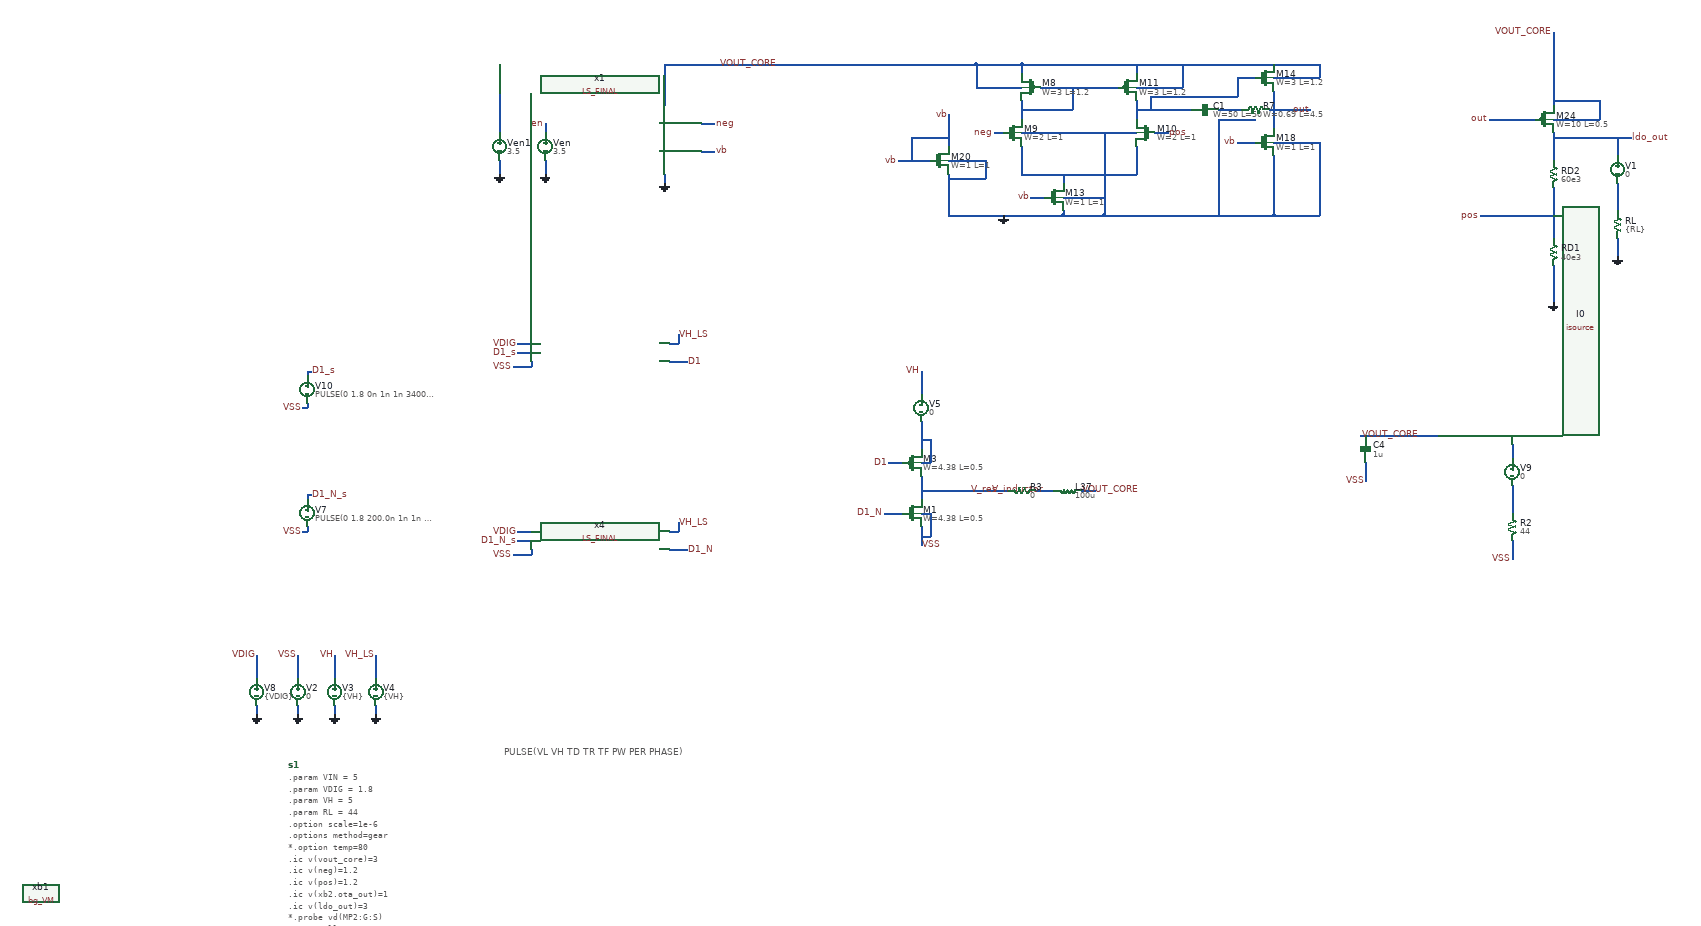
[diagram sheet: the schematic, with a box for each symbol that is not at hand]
v {xschem version=3.4.2 file_version=1.2
}
G {}
K {}
V {}
S {}
E {}
T {PULSE(VL VH TD TR TF PW PER PHASE) } -380 -120 0 0 0.4 0.4 {}
N -830 -210 -830 -190 { lab=GND}
N -830 -320 -830 -270 { lab=VSS}
N -750 -210 -750 -190 { lab=GND}
N -750 -320 -750 -270 { lab=VH}
N 1490 -800 1550 -800 {
lab=VOUT_CORE}
N 1610 -800 1660 -800 {
lab=VOUT_CORE}
N 1550 -800 1610 -800 {
lab=VOUT_CORE}
N 1820 -570 1820 -530 {
lab=VSS}
N 1820 -780 1820 -750 {
lab=#net1}
N -920 -210 -920 -190 { lab=GND}
N -920 -320 -920 -270 { lab=VDIG}
N -660 -210 -660 -190 { lab=GND}
N -660 -320 -660 -270 { lab=VH_LS}
N 1820 -690 1820 -630 {
lab=#net2}
N 1500 -740 1500 -700 {
lab=VSS}
N -290 -1480 -290 -1460 { lab=en}
N -290 -1400 -290 -1370 {
lab=GND}
N -30 -1610 -30 -1520 {
lab=VOUT_CORE}
N 750 -1610 750 -1590 { lab=VOUT_CORE}
N 750 -1610 1000 -1610 { lab=VOUT_CORE}
N 1000 -1610 1000 -1590 { lab=VOUT_CORE}
N 1000 -1530 1000 -1490 { lab=#net3}
N 790 -1560 960 -1560 { lab=#net4}
N 750 -1530 750 -1490 { lab=#net4}
N 750 -1430 750 -1370 { lab=#net5}
N 750 -1370 1000 -1370 { lab=#net5}
N 1000 -1430 1000 -1370 { lab=#net5}
N 840 -1370 840 -1350 { lab=#net5}
N 750 -1460 1000 -1460 { lab=GND}
N 930 -1460 930 -1280 { lab=GND}
N 840 -1280 930 -1280 { lab=GND}
N 1000 -1560 1100 -1560 { lab=VOUT_CORE}
N 1100 -1610 1100 -1560 { lab=VOUT_CORE}
N 990 -1610 1100 -1610 { lab=VOUT_CORE}
N 650 -1560 750 -1560 { lab=VOUT_CORE}
N 650 -1610 650 -1560 { lab=VOUT_CORE}
N 650 -1610 750 -1610 { lab=VOUT_CORE}
N 840 -1320 930 -1320 { lab=GND}
N 1220 -1580 1260 -1580 { lab=#net3}
N 1090 -1610 1220 -1610 { lab=VOUT_CORE}
N 1300 -1580 1400 -1580 { lab=VOUT_CORE}
N 1300 -1610 1400 -1610 { lab=VOUT_CORE}
N 1400 -1610 1400 -1580 { lab=VOUT_CORE}
N 1300 -1550 1300 -1510 { lab=out}
N 930 -1280 1220 -1280 { lab=GND}
N 1300 -1280 1390 -1280 { lab=GND}
N 1220 -1440 1260 -1440 { lab=vb}
N 770 -1320 800 -1320 { lab=vb}
N 860 -1560 860 -1510 { lab=#net4}
N 750 -1510 860 -1510 { lab=#net4}
N 1220 -1510 1230 -1510 { lab=#net6}
N 1290 -1510 1300 -1510 { lab=out}
N 1300 -1510 1300 -1470 { lab=out}
N 1300 -1440 1400 -1440 { lab=GND}
N 1400 -1440 1400 -1280 { lab=GND}
N 1390 -1280 1400 -1280 { lab=GND}
N 1300 -1410 1300 -1280 { lab=GND}
N 690 -1460 710 -1460 { lab=neg}
N 1040 -1460 1070 -1460 { lab=pos}
N 1220 -1580 1220 -1540 { lab=#net3}
N 1000 -1510 1060 -1510 { lab=#net3}
N 1030 -1540 1140 -1540 { lab=#net3}
N 1030 -1540 1030 -1510 { lab=#net3}
N 1300 -1510 1360 -1510 { lab=out}
N 1360 -1510 1370 -1510 { lab=out}
N 1370 -1510 1380 -1510 { lab=out}
N 1240 -1490 1260 -1490 { lab=GND}
N 1180 -1490 1180 -1280 { lab=GND}
N 510 -1400 550 -1400 { lab=vb}
N 510 -1450 510 -1400 { lab=vb}
N 510 -1450 590 -1450 { lab=vb}
N 590 -1370 590 -1350 { lab=GND}
N 590 -1400 670 -1400 { lab=GND}
N 670 -1400 670 -1360 { lab=GND}
N 590 -1360 670 -1360 { lab=GND}
N 480 -1400 510 -1400 { lab=vb}
N 590 -1450 590 -1430 { lab=vb}
N 590 -1500 590 -1450 { lab=vb}
N 840 -1290 840 -1280 { lab=GND}
N 590 -1350 590 -1280 { lab=GND}
N 1140 -1540 1220 -1540 { lab=#net3}
N 1220 -1610 1300 -1610 { lab=VOUT_CORE}
N 1220 -1280 1240 -1280 { lab=GND}
N 1240 -1280 1300 -1280 { lab=GND}
N 1180 -1490 1240 -1490 { lab=GND}
N 1060 -1510 1120 -1510 { lab=#net3}
N 1180 -1510 1220 -1510 { lab=#net6}
N -390 -1480 -390 -1460 { lab=#net7}
N -390 -1400 -390 -1370 {
lab=GND}
N -390 -1610 -390 -1480 {
lab=#net7}
N -30 -1610 550 -1610 {
lab=VOUT_CORE}
N 550 -1610 650 -1610 {
lab=VOUT_CORE}
N 590 -1280 840 -1280 {
lab=GND}
N 2050 -1230 2050 -1190 {
lab=GND}
N 2050 -1350 2050 -1290 {
lab=#net8}
N 1910 -1460 1910 -1440 { lab=ldo_out}
N 1910 -1600 1910 -1520 { lab=VOUT_CORE}
N 1910 -1490 2010 -1490 { lab=VOUT_CORE}
N 1830 -1280 1910 -1280 { lab=pos}
N 1910 -1680 1910 -1600 { lab=VOUT_CORE}
N 1750 -1280 1830 -1280 { lab=pos}
N 2010 -1530 2010 -1490 {
lab=VOUT_CORE}
N 1910 -1530 2010 -1530 {
lab=VOUT_CORE}
N 1770 -1490 1870 -1490 {
lab=out}
N 1910 -1450 2080 -1450 {
lab=ldo_out}
N 2050 -1450 2050 -1410 {
lab=ldo_out}
N 1910 -1440 1910 -1400 {
lab=ldo_out}
N 1910 -1340 1910 -1230 {
lab=pos}
N 1910 -1170 1910 -1090 {
lab=GND}
N -350 -590 -320 -590 {
lab=VDIG}
N -20 -590 0 -590 {
lab=VH_LS}
N 0 -610 0 -590 {
lab=VH_LS}
N -20 -550 20 -550 {
lab=D1_N}
N -350 -1000 -320 -1000 {
lab=VDIG}
N -20 -1000 0 -1000 {
lab=VH_LS}
N 0 -1020 0 -1000 {
lab=VH_LS}
N -20 -960 20 -960 {
lab=D1}
N -350 -980 -320 -980 {
lab=D1_s}
N -350 -570 -320 -570 {
lab=D1_N_s}
N -360 -950 -320 -950 {
lab=VSS}
N -320 -960 -320 -950 {
lab=VSS}
N -360 -540 -320 -540 {
lab=VSS}
N -320 -550 -320 -540 {
lab=VSS}
N -810 -940 -810 -930 {
lab=D1_s}
N -810 -940 -800 -940 {
lab=D1_s}
N -810 -870 -810 -860 {
lab=VSS}
N -820 -860 -810 -860 {
lab=VSS}
N -810 -670 -810 -660 {
lab=D1_N_s}
N -810 -670 -800 -670 {
lab=D1_N_s}
N -810 -600 -810 -590 {
lab=VSS}
N -820 -590 -810 -590 {
lab=VSS}
N 630 -680 700 -680 {
lab=V_res}
N 880 -680 910 -680 {
lab=VOUT_CORE}
N 780 -680 820 -680 {
lab=V_inductor}
N 700 -680 720 -680 {
lab=V_res}
N 530 -680 630 -680 {
lab=V_res}
N 530 -810 530 -770 {
lab=#net9}
N 530 -740 550 -740 {
lab=#net9}
N 550 -790 550 -740 {
lab=#net9}
N 530 -790 550 -790 {
lab=#net9}
N 460 -740 490 -740 {
lab=D1}
N 530 -830 530 -810 {
lab=#net9}
N 530 -600 530 -560 {
lab=VSS}
N 530 -630 550 -630 {
lab=VSS}
N 550 -630 550 -580 {
lab=VSS}
N 530 -580 550 -580 {
lab=VSS}
N 450 -630 490 -630 {
lab=D1_N}
N 530 -710 530 -660 {
lab=V_res}
N 530 -940 530 -890 { lab=VH}
N -30 -1370 -30 -1350 { lab=GND}
N 50 -1480 80 -1480 {
lab=neg}
N 50 -1420 80 -1420 {
lab=vb}
C {devices/vsource.sym} -830 -240 0 0 {name=V2 value=0}
C {devices/gnd.sym} -830 -190 0 0 {name=l9 lab=GND}
C {devices/code_shown.sym} -850 -80 0 0 {name=s1 only_toplevel=false value="
.param VIN = 5
.param VDIG = 1.8
.param VH = 5
.param RL = 44
.option scale=1e-6
.options method=gear
*.option temp=80
.ic v(vout_core)=3

.ic v(neg)=1.2
.ic v(pos)=1.2
.ic v(xb2.ota_out)=1
.ic v(ldo_out)=3

*.probe vd(MP2:G:S)
*.save all
*.save v(d1) v(d2) v(d1top_5v) v(d2_5v) v(d2bot_5v) v(d1bot_5v) v(vout) v(vout_core) v(vdd) v(vh) i(v1) i(v5) i(vmeas) v(v_cftop,v_cfbot)
.save v(D1) v(D2) v(D1_N) v(D2_N) v(VOUT_CORE) v(ldo_out) v(vh) i(v3) i(v10) i(v11) v(v_cftop,v_cfbot) v(D1,v_cftop) v(D2,vout_core) v(D2_N,v_cfbot) v(D1_Nv,VSS) v(v_out_ls1) v(v_out_ls2) v(d2_n,v_cfbot) v(D1_s) v(D2_s) v(D2_N_s) v(D1_N_s) v(V_res) i(v9)
.save @m.xm4.msky130_fd_pr__nfet_g5v0d10v5[vds]
.param mc_mm_switch=0
*.lib /home/jorge/Documents/Postdoc/share/pdk/sky130A/libs.tech/ngspice/sky130.lib.spice tt
*.lib /usr/share/pdk/sky130A/libs.tech/ngspice/sky130.lib.spice ss
*.lib /foss/pdk/sky130A/libs.tech/ngspice/sky130.lib.spice TT
.lib /foss/pdks/sky130A/libs.tech/ngspice/sky130.lib.spice tt
*.include /usr/share/pdk/sky130A/libs.ref/sky130_fd_sc_hvl/spice/sky130_fd_sc_hvl.spice
*.include /home/jorge/Documents/Postdoc/share/pdk/sky130A/libs.ref/sky130_fd_sc_hvl/spice/sky130_fd_sc_hvl.spice
.options savecurrents
.control
*set gmin = 1e-20
*save all
*tran 10n 3000u
*tran 5n 0.6m
tran 5n 400u
*write DCDC_v1p4_5MHz_NMOS_PMOS.raw
*wrdata ~/Documents/Postdoc/chipathon2022/3LFCC_AC3E/xschem/dev_switches/DCDC_5V_FINAL/3LFCC_v1p4.txt tran.v(vout) tran.i(vmeas) tran.v(vdd) tran.i(v3) tran.v(vh) tran.i(v5)
*wrdata /foss/designs/personal/3LFCC_AC3E/xschem/hierarchy_sch/DCDC_5V_FINAL/3LFCC_v1p4.txt tran.v(vout_core) tran.i(v1)
*wrdata /foss/designs/personal/3LFCC_AC3E/xschem/testbench/TopModule/3LFCC_v1p5_topmodule_wfilter_jmtest.txt tran.v(vout_core) tran.i(v3) tran.i(v4) tran.i(v9)
*wrdata /foss/designs/personal/3LFCC_v1p5_topmodule_wfilter_onecore10MHz_3lfcc23.txt tran.v(vout_core) tran.i(v3) tran.i(v4) tran.i(v9)
wrdata /foss/designs/Open3LFCC_V2/tb_DCDCnLDO_wfilter_1core10MHznoCext_open3lfccv2.txt tran.v(vout_core) tran.i(v3) tran.i(v4) tran.i(v9)


*Relación D1 D2 para combinar estados
plot v(D1) v(D2)+5	v(v_cftop,v_cfbot)
*plot v(D1_N) v(D2_N)

*Relación Pulso P y N para acondicionar tiempos muertos (reducir peaks)
plot v(D1) v(D1_N) v(v_cftop,v_cfbot) v(vout_core)
*plot v(D1) v(D1_N)+5 
plot -i(v3)
plot -i(v4)
*plot i(v18) i(v19)
plot i(v10) i(v11)
*plot v(D1) v(D1_N)	 v(D2) v(D2_N) i(v3) v(v_cftop,v_cfbot)
plot v(D1_N_s) v(D2_N_s)+2 v(D2_s)+4 v(D1_s)+6 i(v3)
plot v(D1_N_s) v(D1_s) v(D2_N_s) v(D2_s) i(v3)
plot v(V_res)
plot v(v_cftop,v_cfbot)
plot i(v9)
plot v(vout_core)
plot v(vout_core) v(ldo_out)

let id20  = @m.xm20.msky130_fd_pr__nfet_g5v0d10v5[id]
plot id20


*Revisión de estados del convertidor en base a señal de Flycap (caso Cap_ext omitido para ver bien formas de onda de flycap)
*plot v(v_cftop,v_cfbot) v(vout_core) i(v3)

*plot v(v_cftop,v_cfbot) v(D1) v(D2)
*plot v(v_cftop,v_cfbot) v(D2) v(D2_N)
*plot v(v_cftop,v_cfbot) v(D1) v(D1_N)
*plot v(v_cftop,v_cfbot) v(vout_core) 

**Problema actual, eficiencia no se logra calcular debido a que no transicionan bien todo los estados, (Cuando el Flycap esta flotante no esta consumiendo energía, es decir la carga no esta conectada a la fuente de entrada...)
** Si bien D1- D1_N y D2- D2_N estan con sus respectivos tiempos muertos (redución de peaks), falta sincronizar bien D1 con D2 para lograr la conexión correcta para que la carga se conecte a la fuente en estado de flycap flotante.

.endc
"}
C {devices/vsource.sym} -750 -240 0 0 {name=V3 value=\{VH\}}
C {devices/gnd.sym} -750 -190 0 0 {name=l23 lab=GND}
C {devices/lab_wire.sym} -750 -320 0 0 {name=l24 sig_type=std_logic lab=VH}
C {devices/isource.sym} 1690 -740 0 0 {name=I0 value=0.15
}
C {devices/lab_wire.sym} 1820 -530 0 0 {name=l1 sig_type=std_logic lab=VSS}
C {devices/res.sym} 1820 -600 0 0 {name=R2
value=44
footprint=1206
device=resistor
m=1}
C {devices/vsource.sym} -920 -240 0 0 {name=V8 value=\{VDIG\}}
C {devices/gnd.sym} -920 -190 0 0 {name=l23 lab=GND}
C {devices/lab_wire.sym} -920 -320 0 0 {name=l24 sig_type=std_logic lab=VDIG}
C {devices/lab_wire.sym} -830 -320 0 0 {name=l15 sig_type=std_logic lab=VSS}
C {devices/vsource.sym} -660 -240 0 0 {name=V4 value=\{VH\}}
C {devices/gnd.sym} -660 -190 0 0 {name=l23 lab=GND}
C {devices/lab_wire.sym} -660 -320 0 0 {name=l24 sig_type=std_logic lab=VH_LS}
C {devices/vsource.sym} 1820 -720 0 0 {name=V9 value=0}
C {devices/capa.sym} 1500 -770 0 0 {name=C4
m=1
value=1u
footprint=1206
device="ceramic capacitor"}
C {devices/lab_wire.sym} 1500 -700 0 0 {name=l19 sig_type=std_logic lab=VSS}
C {devices/lab_wire.sym} 1490 -800 0 1 {name=l29 sig_type=std_logic lab=VOUT_CORE}
C {devices/vsource.sym} -290 -1430 0 0 {name=Ven value=3.5}
C {devices/lab_pin.sym} -290 -1480 0 0 {name=l46 sig_type=std_logic lab=en}
C {devices/gnd.sym} -290 -1370 0 0 {name=l48 lab=GND}
C {devices/gnd.sym} 710 -1280 0 0 {name=l2 lab=GND}
C {sky130_fd_pr/pfet_g5v0d10v5.sym} 770 -1560 0 1 {name=M8
L=1.2
W=3
nf=1
mult=4
ad="'int((nf+1)/2) * W/nf * 0.29'" 
pd="'2*int((nf+1)/2) * (W/nf + 0.29)'"
as="'int((nf+2)/2) * W/nf * 0.29'" 
ps="'2*int((nf+2)/2) * (W/nf + 0.29)'"
nrd="'0.29 / W'" nrs="'0.29 / W'"
sa=0 sb=0 sd=0
model=pfet_g5v0d10v5
spiceprefix=X
}
C {sky130_fd_pr/nfet_g5v0d10v5.sym} 730 -1460 0 0 {name=M9
L=1
W=2
nf=1
mult=8
ad="'int((nf+1)/2) * W/nf * 0.29'" 
pd="'2*int((nf+1)/2) * (W/nf + 0.29)'"
as="'int((nf+2)/2) * W/nf * 0.29'" 
ps="'2*int((nf+2)/2) * (W/nf + 0.29)'"
nrd="'0.29 / W'" nrs="'0.29 / W'"
sa=0 sb=0 sd=0
model=nfet_g5v0d10v5
spiceprefix=X
}
C {sky130_fd_pr/nfet_g5v0d10v5.sym} 1020 -1460 0 1 {name=M10
L=1
W=2
nf=1
mult=8
ad="'int((nf+1)/2) * W/nf * 0.29'" 
pd="'2*int((nf+1)/2) * (W/nf + 0.29)'"
as="'int((nf+2)/2) * W/nf * 0.29'" 
ps="'2*int((nf+2)/2) * (W/nf + 0.29)'"
nrd="'0.29 / W'" nrs="'0.29 / W'"
sa=0 sb=0 sd=0
model=nfet_g5v0d10v5
spiceprefix=X
}
C {sky130_fd_pr/pfet_g5v0d10v5.sym} 980 -1560 0 0 {name=M11
L=1.2
W=3
nf=1
mult=4
ad="'int((nf+1)/2) * W/nf * 0.29'" 
pd="'2*int((nf+1)/2) * (W/nf + 0.29)'"
as="'int((nf+2)/2) * W/nf * 0.29'" 
ps="'2*int((nf+2)/2) * (W/nf + 0.29)'"
nrd="'0.29 / W'" nrs="'0.29 / W'"
sa=0 sb=0 sd=0
model=pfet_g5v0d10v5
spiceprefix=X
}
C {sky130_fd_pr/nfet_g5v0d10v5.sym} 820 -1320 0 0 {name=M13
L=1
W=1
nf=1
mult=8
ad="'int((nf+1)/2) * W/nf * 0.29'" 
pd="'2*int((nf+1)/2) * (W/nf + 0.29)'"
as="'int((nf+2)/2) * W/nf * 0.29'" 
ps="'2*int((nf+2)/2) * (W/nf + 0.29)'"
nrd="'0.29 / W'" nrs="'0.29 / W'"
sa=0 sb=0 sd=0
model=nfet_g5v0d10v5
spiceprefix=X
}
C {sky130_fd_pr/pfet_g5v0d10v5.sym} 1280 -1580 0 0 {name=M14
L=1.2
W=3
nf=1
mult=12
ad="'int((nf+1)/2) * W/nf * 0.29'" 
pd="'2*int((nf+1)/2) * (W/nf + 0.29)'"
as="'int((nf+2)/2) * W/nf * 0.29'" 
ps="'2*int((nf+2)/2) * (W/nf + 0.29)'"
nrd="'0.29 / W'" nrs="'0.29 / W'"
sa=0 sb=0 sd=0
model=pfet_g5v0d10v5
spiceprefix=X
}
C {sky130_fd_pr/nfet_g5v0d10v5.sym} 1280 -1440 0 0 {name=M18
L=1
W=1
nf=1
mult=12
ad="'int((nf+1)/2) * W/nf * 0.29'" 
pd="'2*int((nf+1)/2) * (W/nf + 0.29)'"
as="'int((nf+2)/2) * W/nf * 0.29'" 
ps="'2*int((nf+2)/2) * (W/nf + 0.29)'"
nrd="'0.29 / W'" nrs="'0.29 / W'"
sa=0 sb=0 sd=0
model=nfet_g5v0d10v5
spiceprefix=X
}
C {devices/lab_pin.sym} 770 -1320 0 0 {name=l3 sig_type=std_logic lab=vb}
C {devices/lab_pin.sym} 1220 -1440 0 0 {name=l32 sig_type=std_logic lab=vb}
C {sky130_fd_pr/cap_mim_m3_1.sym} 1150 -1510 3 1 {name=C1 model=cap_mim_m3_1 W=50 L=50 MF=1 spiceprefix=X}
C {sky130_fd_pr/res_xhigh_po_0p69.sym} 1260 -1510 3 0 {name=R7
W=0.69
L=4.5
model=res_xhigh_po_0p69
spiceprefix=X
mult=1}
C {sky130_fd_pr/nfet_g5v0d10v5.sym} 570 -1400 0 0 {name=M20
L=1
W=1
nf=1
mult=4
ad="'int((nf+1)/2) * W/nf * 0.29'" 
pd="'2*int((nf+1)/2) * (W/nf + 0.29)'"
as="'int((nf+2)/2) * W/nf * 0.29'" 
ps="'2*int((nf+2)/2) * (W/nf + 0.29)'"
nrd="'0.29 / W'" nrs="'0.29 / W'"
sa=0 sb=0 sd=0
model=nfet_g5v0d10v5
spiceprefix=X
}
C {devices/lab_pin.sym} 480 -1400 0 0 {name=l40 sig_type=std_logic lab=vb}
C {devices/lab_pin.sym} 590 -1500 0 0 {name=l41 sig_type=std_logic lab=vb}
C {devices/lab_pin.sym} 690 -1460 0 0 {name=p5 sig_type=std_logic lab=neg
}
C {devices/lab_pin.sym} 1380 -1510 0 0 {name=l49 sig_type=std_logic lab=out}
C {devices/lab_pin.sym} 1070 -1460 2 0 {name=p2 sig_type=std_logic lab=pos

}
C {devices/vsource.sym} -390 -1430 0 0 {name=Ven1 value=3.5}
C {devices/gnd.sym} -390 -1370 0 0 {name=l47 lab=GND}
C {devices/res.sym} 2050 -1260 0 0 {name=RL
value=\{RL\}
footprint=1206
device=resistor
m=1}
C {devices/vsource.sym} 2050 -1380 0 0 {name=V1 value=0}
C {sky130_fd_pr/pfet_g5v0d10v5.sym} 1890 -1490 0 0 {name=M24
L=0.5
W=10
nf=1
mult=800
ad="'int((nf+1)/2) * W/nf * 0.29'" 
pd="'2*int((nf+1)/2) * (W/nf + 0.29)'"
as="'int((nf+2)/2) * W/nf * 0.29'" 
ps="'2*int((nf+2)/2) * (W/nf + 0.29)'"
nrd="'0.29 / W'" nrs="'0.29 / W'"
sa=0 sb=0 sd=0
model=pfet_g5v0d10v5
spiceprefix=X
}
C {devices/gnd.sym} 2050 -1190 0 0 {name=l52 lab=GND}
C {devices/lab_pin.sym} 1770 -1490 0 0 {name=l53 sig_type=std_logic lab=out}
C {devices/lab_pin.sym} 1750 -1280 0 0 {name=p3 sig_type=std_logic lab=pos

}
C {devices/lab_pin.sym} 2080 -1450 2 0 {name=p1 sig_type=std_logic lab=ldo_out

}
C {devices/lab_wire.sym} 1910 -1680 3 1 {name=l54 sig_type=std_logic lab=VOUT_CORE}
C {devices/gnd.sym} 1910 -1090 0 0 {name=l55 lab=GND}
C {devices/res.sym} 1910 -1370 0 0 {name=RD2
value=60e3
footprint=1206
device=resistor
m=1}
C {devices/res.sym} 1910 -1200 0 0 {name=RD1
value=40e3
footprint=1206
device=resistor
m=1}
C {devices/lab_wire.sym} 90 -1610 0 1 {name=l58 sig_type=std_logic lab=VOUT_CORE}
C {devices/lab_pin.sym} -350 -570 2 1 {name=l14 sig_type=std_logic lab=D1_N_s
}
C {devices/lab_wire.sym} -350 -590 0 0 {name=l4 sig_type=std_logic lab=VDIG}
C {devices/lab_pin.sym} 20 -550 0 1 {name=l6 sig_type=std_logic lab=D1_N
}
C {devices/lab_pin.sym} -350 -980 2 1 {name=l5 sig_type=std_logic lab=D1_s
}
C {devices/lab_wire.sym} -350 -1000 0 0 {name=l11 sig_type=std_logic lab=VDIG}
C {devices/lab_pin.sym} 0 -1020 0 1 {name=l125 sig_type=std_logic lab=VH_LS
}
C {devices/lab_pin.sym} 20 -960 0 1 {name=l12 sig_type=std_logic lab=D1
}
C {devices/lab_wire.sym} -360 -950 0 0 {name=l7 sig_type=std_logic lab=VSS}
C {devices/lab_wire.sym} -360 -540 0 0 {name=l31 sig_type=std_logic lab=VSS}
C {devices/lab_pin.sym} 0 -610 0 1 {name=l36 sig_type=std_logic lab=VH_LS
}
C {LS_FINAL.sym} -170 -980 0 0 {name=x1}
C {LS_FINAL.sym} -170 -570 0 0 {name=x4}
C {devices/lab_wire.sym} -800 -940 0 1 {name=l8 sig_type=std_logic lab=D1_s}
C {devices/vsource.sym} -810 -630 0 0 {name=V7 value="PULSE(0 1.8 200.0n 1n 1n 3000.0000000000005n 10000.0n)"}
C {devices/lab_pin.sym} -800 -670 0 1 {name=l10 sig_type=std_logic lab=D1_N_s
}
C {devices/lab_wire.sym} -820 -590 0 0 {name=l13 sig_type=std_logic lab=VSS}
C {devices/lab_wire.sym} -820 -860 0 0 {name=l16 sig_type=std_logic lab=VSS}
C {devices/vsource.sym} -810 -900 0 0 {name=V10 value="PULSE(0 1.8 0n 1n 1n 3400.0000000000005n 10000.0n)"}
C {devices/lab_wire.sym} 880 -680 0 1 {name=l17 sig_type=std_logic lab=VOUT_CORE}
C {devices/ind.sym} 850 -680 1 0 {name=L37
m=1
value=100u
footprint=1206
device=inductor}
C {devices/lab_wire.sym} 800 -680 1 1 {name=l38 sig_type=std_logic lab=V_inductor}
C {devices/res.sym} 750 -680 1 0 {name=R3
value=0
footprint=1206
device=resistor
m=1}
C {devices/lab_wire.sym} 700 -680 1 1 {name=l39 sig_type=std_logic lab=V_res}
C {sky130_fd_pr/pfet_g5v0d10v5.sym} 510 -740 0 0 {name=M3
L=0.5
W=4.38
nf=1
mult=4506
ad="'int((nf+1)/2) * W/nf * 0.29'" 
pd="'2*int((nf+1)/2) * (W/nf + 0.29)'"
as="'int((nf+2)/2) * W/nf * 0.29'" 
ps="'2*int((nf+2)/2) * (W/nf + 0.29)'"
nrd="'0.29 / W'" nrs="'0.29 / W'"
sa=0 sb=0 sd=0
model=pfet_g5v0d10v5
spiceprefix=X
}
C {sky130_fd_pr/nfet_g5v0d10v5.sym} 510 -630 0 0 {name=M1
L=0.5
W=4.38
nf=1
mult=2520
ad="'int((nf+1)/2) * W/nf * 0.29'" 
pd="'2*int((nf+1)/2) * (W/nf + 0.29)'"
as="'int((nf+2)/2) * W/nf * 0.29'" 
ps="'2*int((nf+2)/2) * (W/nf + 0.29)'"
nrd="'0.29 / W'" nrs="'0.29 / W'"
sa=0 sb=0 sd=0
model=nfet_g5v0d10v5
spiceprefix=X
}
C {devices/vsource.sym} 530 -860 0 0 {name=V5 value=0}
C {devices/lab_wire.sym} 530 -940 0 0 {name=l18 sig_type=std_logic lab=VH}
C {devices/lab_wire.sym} 530 -560 2 0 {name=l20 sig_type=std_logic lab=VSS}
C {devices/lab_pin.sym} 460 -740 0 0 {name=l21 sig_type=std_logic lab=D1
}
C {devices/lab_pin.sym} 450 -630 0 0 {name=l22 sig_type=std_logic lab=D1_N
}
C {devices/gnd.sym} -30 -1350 0 0 {name=l25 lab=GND}
C {devices/lab_pin.sym} 80 -1480 2 0 {name=l26 sig_type=std_logic lab=neg}
C {devices/lab_pin.sym} 80 -1420 2 0 {name=l27 sig_type=std_logic lab=vb}
C {/foss/designs/Open3LFCC_V2/ldo_new_bg_DA_20230921/bg_VM.sym} -1390 200 0 0 {name=xb1}
